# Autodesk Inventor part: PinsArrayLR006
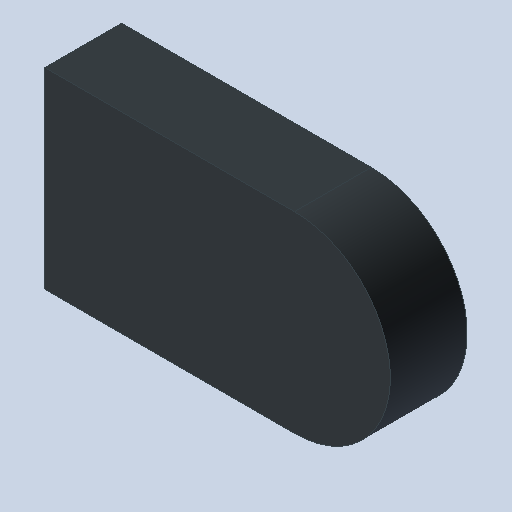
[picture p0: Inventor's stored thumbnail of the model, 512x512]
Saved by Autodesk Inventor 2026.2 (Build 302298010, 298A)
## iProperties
Created: 2026-10
Part Number: PinsArrayLR006
Material: Générique
Document SubType Name: Modeling
Designer: mel
Density: 1 g/cm^3
Appearance: Par défaut
Author: mel
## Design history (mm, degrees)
feature "Base1"
node "Solide1"
